VERSION 5.7 ;
  NOWIREEXTENSIONATPIN ON ;
  DIVIDERCHAR "/" ;
  BUSBITCHARS "[]" ;
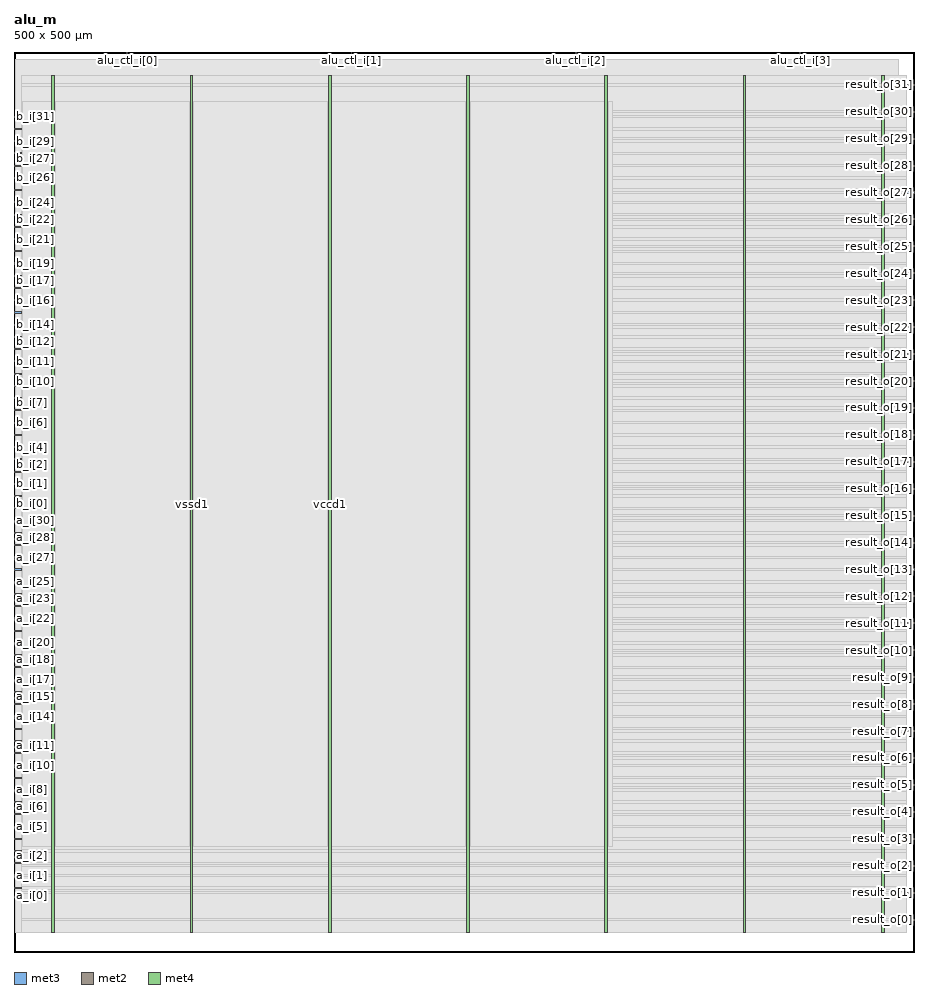
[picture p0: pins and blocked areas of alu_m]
MACRO alu_m
  CLASS BLOCK ;
  FOREIGN alu_m ;
  ORIGIN 0.000 0.000 ;
  SIZE 500.000 BY 500.000 ;
  PIN a_i[0]
    DIRECTION INPUT ;
    USE SIGNAL ;
    ANTENNAGATEAREA 0.213000 ;
    PORT
      LAYER met3 ;
        RECT 0.000 35.400 4.000 36.000 ;
    END
  END a_i[0]
  PIN a_i[10]
    DIRECTION INPUT ;
    USE SIGNAL ;
    ANTENNAGATEAREA 0.196500 ;
    PORT
      LAYER met3 ;
        RECT 0.000 103.400 4.000 104.000 ;
    END
  END a_i[10]
  PIN a_i[11]
    DIRECTION INPUT ;
    USE SIGNAL ;
    ANTENNAGATEAREA 0.196500 ;
    PORT
      LAYER met3 ;
        RECT 0.000 110.200 4.000 110.800 ;
    END
  END a_i[11]
  PIN a_i[12]
    DIRECTION INPUT ;
    USE SIGNAL ;
    ANTENNAGATEAREA 0.213000 ;
    PORT
      LAYER met3 ;
        RECT 0.000 117.000 4.000 117.600 ;
    END
  END a_i[12]
  PIN a_i[13]
    DIRECTION INPUT ;
    USE SIGNAL ;
    ANTENNAGATEAREA 0.213000 ;
    PORT
      LAYER met3 ;
        RECT 0.000 123.800 4.000 124.400 ;
    END
  END a_i[13]
  PIN a_i[14]
    DIRECTION INPUT ;
    USE SIGNAL ;
    ANTENNAGATEAREA 0.196500 ;
    PORT
      LAYER met3 ;
        RECT 0.000 130.600 4.000 131.200 ;
    END
  END a_i[14]
  PIN a_i[15]
    DIRECTION INPUT ;
    USE SIGNAL ;
    ANTENNAGATEAREA 0.196500 ;
    PORT
      LAYER met3 ;
        RECT 0.000 137.400 4.000 138.000 ;
    END
  END a_i[15]
  PIN a_i[16]
    DIRECTION INPUT ;
    USE SIGNAL ;
    ANTENNAGATEAREA 0.196500 ;
    PORT
      LAYER met3 ;
        RECT 0.000 144.200 4.000 144.800 ;
    END
  END a_i[16]
  PIN a_i[17]
    DIRECTION INPUT ;
    USE SIGNAL ;
    ANTENNAGATEAREA 0.196500 ;
    PORT
      LAYER met3 ;
        RECT 0.000 151.000 4.000 151.600 ;
    END
  END a_i[17]
  PIN a_i[18]
    DIRECTION INPUT ;
    USE SIGNAL ;
    ANTENNAGATEAREA 0.196500 ;
    PORT
      LAYER met3 ;
        RECT 0.000 157.800 4.000 158.400 ;
    END
  END a_i[18]
  PIN a_i[19]
    DIRECTION INPUT ;
    USE SIGNAL ;
    ANTENNAGATEAREA 0.196500 ;
    PORT
      LAYER met3 ;
        RECT 0.000 164.600 4.000 165.200 ;
    END
  END a_i[19]
  PIN a_i[1]
    DIRECTION INPUT ;
    USE SIGNAL ;
    ANTENNAGATEAREA 0.247500 ;
    PORT
      LAYER met3 ;
        RECT 0.000 42.200 4.000 42.800 ;
    END
  END a_i[1]
  PIN a_i[20]
    DIRECTION INPUT ;
    USE SIGNAL ;
    ANTENNAGATEAREA 0.196500 ;
    PORT
      LAYER met3 ;
        RECT 0.000 171.400 4.000 172.000 ;
    END
  END a_i[20]
  PIN a_i[21]
    DIRECTION INPUT ;
    USE SIGNAL ;
    ANTENNAGATEAREA 0.196500 ;
    PORT
      LAYER met3 ;
        RECT 0.000 178.200 4.000 178.800 ;
    END
  END a_i[21]
  PIN a_i[22]
    DIRECTION INPUT ;
    USE SIGNAL ;
    ANTENNAGATEAREA 0.196500 ;
    PORT
      LAYER met3 ;
        RECT 0.000 185.000 4.000 185.600 ;
    END
  END a_i[22]
  PIN a_i[23]
    DIRECTION INPUT ;
    USE SIGNAL ;
    ANTENNAGATEAREA 0.196500 ;
    PORT
      LAYER met3 ;
        RECT 0.000 191.800 4.000 192.400 ;
    END
  END a_i[23]
  PIN a_i[24]
    DIRECTION INPUT ;
    USE SIGNAL ;
    ANTENNAGATEAREA 0.196500 ;
    PORT
      LAYER met3 ;
        RECT 0.000 198.600 4.000 199.200 ;
    END
  END a_i[24]
  PIN a_i[25]
    DIRECTION INPUT ;
    USE SIGNAL ;
    ANTENNAGATEAREA 0.247500 ;
    PORT
      LAYER met3 ;
        RECT 0.000 205.400 4.000 206.000 ;
    END
  END a_i[25]
  PIN a_i[26]
    DIRECTION INPUT ;
    USE SIGNAL ;
    ANTENNAGATEAREA 0.213000 ;
    PORT
      LAYER met3 ;
        RECT 0.000 212.200 4.000 212.800 ;
    END
  END a_i[26]
  PIN a_i[27]
    DIRECTION INPUT ;
    USE SIGNAL ;
    ANTENNAGATEAREA 0.159000 ;
    PORT
      LAYER met3 ;
        RECT 0.000 219.000 4.000 219.600 ;
    END
  END a_i[27]
  PIN a_i[28]
    DIRECTION INPUT ;
    USE SIGNAL ;
    ANTENNAGATEAREA 0.159000 ;
    PORT
      LAYER met3 ;
        RECT 0.000 225.800 4.000 226.400 ;
    END
  END a_i[28]
  PIN a_i[29]
    DIRECTION INPUT ;
    USE SIGNAL ;
    ANTENNAGATEAREA 0.213000 ;
    PORT
      LAYER met3 ;
        RECT 0.000 232.600 4.000 233.200 ;
    END
  END a_i[29]
  PIN a_i[2]
    DIRECTION INPUT ;
    USE SIGNAL ;
    ANTENNAGATEAREA 0.159000 ;
    PORT
      LAYER met3 ;
        RECT 0.000 49.000 4.000 49.600 ;
    END
  END a_i[2]
  PIN a_i[30]
    DIRECTION INPUT ;
    USE SIGNAL ;
    ANTENNAGATEAREA 0.159000 ;
    PORT
      LAYER met3 ;
        RECT 0.000 239.400 4.000 240.000 ;
    END
  END a_i[30]
  PIN a_i[31]
    DIRECTION INPUT ;
    USE SIGNAL ;
    ANTENNAGATEAREA 0.213000 ;
    PORT
      LAYER met3 ;
        RECT 0.000 246.200 4.000 246.800 ;
    END
  END a_i[31]
  PIN a_i[3]
    DIRECTION INPUT ;
    USE SIGNAL ;
    ANTENNAGATEAREA 0.213000 ;
    PORT
      LAYER met3 ;
        RECT 0.000 55.800 4.000 56.400 ;
    END
  END a_i[3]
  PIN a_i[4]
    DIRECTION INPUT ;
    USE SIGNAL ;
    ANTENNAGATEAREA 0.159000 ;
    PORT
      LAYER met3 ;
        RECT 0.000 62.600 4.000 63.200 ;
    END
  END a_i[4]
  PIN a_i[5]
    DIRECTION INPUT ;
    USE SIGNAL ;
    ANTENNAGATEAREA 0.159000 ;
    PORT
      LAYER met3 ;
        RECT 0.000 69.400 4.000 70.000 ;
    END
  END a_i[5]
  PIN a_i[6]
    DIRECTION INPUT ;
    USE SIGNAL ;
    ANTENNAGATEAREA 0.213000 ;
    PORT
      LAYER met3 ;
        RECT 0.000 76.200 4.000 76.800 ;
    END
  END a_i[6]
  PIN a_i[7]
    DIRECTION INPUT ;
    USE SIGNAL ;
    ANTENNAGATEAREA 0.213000 ;
    PORT
      LAYER met3 ;
        RECT 0.000 83.000 4.000 83.600 ;
    END
  END a_i[7]
  PIN a_i[8]
    DIRECTION INPUT ;
    USE SIGNAL ;
    ANTENNAGATEAREA 0.213000 ;
    PORT
      LAYER met3 ;
        RECT 0.000 89.800 4.000 90.400 ;
    END
  END a_i[8]
  PIN a_i[9]
    DIRECTION INPUT ;
    USE SIGNAL ;
    ANTENNAGATEAREA 0.196500 ;
    PORT
      LAYER met3 ;
        RECT 0.000 96.600 4.000 97.200 ;
    END
  END a_i[9]
  PIN alu_ctl_i[0]
    DIRECTION INPUT ;
    USE SIGNAL ;
    ANTENNAGATEAREA 0.213000 ;
    PORT
      LAYER met2 ;
        RECT 62.650 496.000 62.930 500.000 ;
    END
  END alu_ctl_i[0]
  PIN alu_ctl_i[1]
    DIRECTION INPUT ;
    USE SIGNAL ;
    ANTENNAGATEAREA 0.213000 ;
    PORT
      LAYER met2 ;
        RECT 187.310 496.000 187.590 500.000 ;
    END
  END alu_ctl_i[1]
  PIN alu_ctl_i[2]
    DIRECTION INPUT ;
    USE SIGNAL ;
    ANTENNAGATEAREA 0.213000 ;
    PORT
      LAYER met2 ;
        RECT 311.970 496.000 312.250 500.000 ;
    END
  END alu_ctl_i[2]
  PIN alu_ctl_i[3]
    DIRECTION INPUT ;
    USE SIGNAL ;
    ANTENNAGATEAREA 0.213000 ;
    PORT
      LAYER met2 ;
        RECT 436.630 496.000 436.910 500.000 ;
    END
  END alu_ctl_i[3]
  PIN b_i[0]
    DIRECTION INPUT ;
    USE SIGNAL ;
    ANTENNAGATEAREA 0.196500 ;
    PORT
      LAYER met3 ;
        RECT 0.000 253.000 4.000 253.600 ;
    END
  END b_i[0]
  PIN b_i[10]
    DIRECTION INPUT ;
    USE SIGNAL ;
    ANTENNAGATEAREA 0.213000 ;
    PORT
      LAYER met3 ;
        RECT 0.000 321.000 4.000 321.600 ;
    END
  END b_i[10]
  PIN b_i[11]
    DIRECTION INPUT ;
    USE SIGNAL ;
    ANTENNAGATEAREA 0.159000 ;
    PORT
      LAYER met3 ;
        RECT 0.000 327.800 4.000 328.400 ;
    END
  END b_i[11]
  PIN b_i[12]
    DIRECTION INPUT ;
    USE SIGNAL ;
    ANTENNAGATEAREA 0.213000 ;
    PORT
      LAYER met3 ;
        RECT 0.000 334.600 4.000 335.200 ;
    END
  END b_i[12]
  PIN b_i[13]
    DIRECTION INPUT ;
    USE SIGNAL ;
    ANTENNAGATEAREA 0.213000 ;
    PORT
      LAYER met3 ;
        RECT 0.000 341.400 4.000 342.000 ;
    END
  END b_i[13]
  PIN b_i[14]
    DIRECTION INPUT ;
    USE SIGNAL ;
    ANTENNAGATEAREA 0.159000 ;
    PORT
      LAYER met3 ;
        RECT 0.000 348.200 4.000 348.800 ;
    END
  END b_i[14]
  PIN b_i[15]
    DIRECTION INPUT ;
    USE SIGNAL ;
    ANTENNAGATEAREA 0.159000 ;
    PORT
      LAYER met3 ;
        RECT 0.000 355.000 4.000 355.600 ;
    END
  END b_i[15]
  PIN b_i[16]
    DIRECTION INPUT ;
    USE SIGNAL ;
    ANTENNAGATEAREA 0.159000 ;
    PORT
      LAYER met3 ;
        RECT 0.000 361.800 4.000 362.400 ;
    END
  END b_i[16]
  PIN b_i[17]
    DIRECTION INPUT ;
    USE SIGNAL ;
    ANTENNAGATEAREA 0.196500 ;
    PORT
      LAYER met3 ;
        RECT 0.000 368.600 4.000 369.200 ;
    END
  END b_i[17]
  PIN b_i[18]
    DIRECTION INPUT ;
    USE SIGNAL ;
    ANTENNAGATEAREA 0.196500 ;
    PORT
      LAYER met3 ;
        RECT 0.000 375.400 4.000 376.000 ;
    END
  END b_i[18]
  PIN b_i[19]
    DIRECTION INPUT ;
    USE SIGNAL ;
    ANTENNAGATEAREA 0.196500 ;
    PORT
      LAYER met3 ;
        RECT 0.000 382.200 4.000 382.800 ;
    END
  END b_i[19]
  PIN b_i[1]
    DIRECTION INPUT ;
    USE SIGNAL ;
    ANTENNAGATEAREA 0.196500 ;
    PORT
      LAYER met3 ;
        RECT 0.000 259.800 4.000 260.400 ;
    END
  END b_i[1]
  PIN b_i[20]
    DIRECTION INPUT ;
    USE SIGNAL ;
    ANTENNAGATEAREA 0.196500 ;
    PORT
      LAYER met3 ;
        RECT 0.000 389.000 4.000 389.600 ;
    END
  END b_i[20]
  PIN b_i[21]
    DIRECTION INPUT ;
    USE SIGNAL ;
    ANTENNAGATEAREA 0.196500 ;
    PORT
      LAYER met3 ;
        RECT 0.000 395.800 4.000 396.400 ;
    END
  END b_i[21]
  PIN b_i[22]
    DIRECTION INPUT ;
    USE SIGNAL ;
    ANTENNAGATEAREA 0.196500 ;
    PORT
      LAYER met3 ;
        RECT 0.000 402.600 4.000 403.200 ;
    END
  END b_i[22]
  PIN b_i[23]
    DIRECTION INPUT ;
    USE SIGNAL ;
    ANTENNAGATEAREA 0.196500 ;
    PORT
      LAYER met3 ;
        RECT 0.000 409.400 4.000 410.000 ;
    END
  END b_i[23]
  PIN b_i[24]
    DIRECTION INPUT ;
    USE SIGNAL ;
    ANTENNAGATEAREA 0.196500 ;
    PORT
      LAYER met3 ;
        RECT 0.000 416.200 4.000 416.800 ;
    END
  END b_i[24]
  PIN b_i[25]
    DIRECTION INPUT ;
    USE SIGNAL ;
    ANTENNAGATEAREA 0.196500 ;
    PORT
      LAYER met3 ;
        RECT 0.000 423.000 4.000 423.600 ;
    END
  END b_i[25]
  PIN b_i[26]
    DIRECTION INPUT ;
    USE SIGNAL ;
    ANTENNAGATEAREA 0.247500 ;
    PORT
      LAYER met3 ;
        RECT 0.000 429.800 4.000 430.400 ;
    END
  END b_i[26]
  PIN b_i[27]
    DIRECTION INPUT ;
    USE SIGNAL ;
    ANTENNAGATEAREA 0.247500 ;
    PORT
      LAYER met3 ;
        RECT 0.000 436.600 4.000 437.200 ;
    END
  END b_i[27]
  PIN b_i[28]
    DIRECTION INPUT ;
    USE SIGNAL ;
    ANTENNAGATEAREA 0.196500 ;
    PORT
      LAYER met3 ;
        RECT 0.000 443.400 4.000 444.000 ;
    END
  END b_i[28]
  PIN b_i[29]
    DIRECTION INPUT ;
    USE SIGNAL ;
    ANTENNAGATEAREA 0.159000 ;
    PORT
      LAYER met3 ;
        RECT 0.000 450.200 4.000 450.800 ;
    END
  END b_i[29]
  PIN b_i[2]
    DIRECTION INPUT ;
    USE SIGNAL ;
    ANTENNAGATEAREA 0.159000 ;
    PORT
      LAYER met3 ;
        RECT 0.000 266.600 4.000 267.200 ;
    END
  END b_i[2]
  PIN b_i[30]
    DIRECTION INPUT ;
    USE SIGNAL ;
    ANTENNAGATEAREA 0.196500 ;
    PORT
      LAYER met3 ;
        RECT 0.000 457.000 4.000 457.600 ;
    END
  END b_i[30]
  PIN b_i[31]
    DIRECTION INPUT ;
    USE SIGNAL ;
    ANTENNAGATEAREA 0.213000 ;
    PORT
      LAYER met3 ;
        RECT 0.000 463.800 4.000 464.400 ;
    END
  END b_i[31]
  PIN b_i[3]
    DIRECTION INPUT ;
    USE SIGNAL ;
    ANTENNAGATEAREA 0.159000 ;
    PORT
      LAYER met3 ;
        RECT 0.000 273.400 4.000 274.000 ;
    END
  END b_i[3]
  PIN b_i[4]
    DIRECTION INPUT ;
    USE SIGNAL ;
    ANTENNAGATEAREA 0.213000 ;
    PORT
      LAYER met3 ;
        RECT 0.000 280.200 4.000 280.800 ;
    END
  END b_i[4]
  PIN b_i[5]
    DIRECTION INPUT ;
    USE SIGNAL ;
    ANTENNAGATEAREA 0.213000 ;
    PORT
      LAYER met3 ;
        RECT 0.000 287.000 4.000 287.600 ;
    END
  END b_i[5]
  PIN b_i[6]
    DIRECTION INPUT ;
    USE SIGNAL ;
    ANTENNAGATEAREA 0.247500 ;
    PORT
      LAYER met3 ;
        RECT 0.000 293.800 4.000 294.400 ;
    END
  END b_i[6]
  PIN b_i[7]
    DIRECTION INPUT ;
    USE SIGNAL ;
    ANTENNAGATEAREA 0.213000 ;
    PORT
      LAYER met3 ;
        RECT 0.000 300.600 4.000 301.200 ;
    END
  END b_i[7]
  PIN b_i[8]
    DIRECTION INPUT ;
    USE SIGNAL ;
    ANTENNAGATEAREA 0.213000 ;
    PORT
      LAYER met3 ;
        RECT 0.000 307.400 4.000 308.000 ;
    END
  END b_i[8]
  PIN b_i[9]
    DIRECTION INPUT ;
    USE SIGNAL ;
    ANTENNAGATEAREA 0.247500 ;
    PORT
      LAYER met3 ;
        RECT 0.000 314.200 4.000 314.800 ;
    END
  END b_i[9]
  PIN result_o[0]
    DIRECTION OUTPUT TRISTATE ;
    USE SIGNAL ;
    ANTENNADIFFAREA 2.673000 ;
    PORT
      LAYER met3 ;
        RECT 496.000 17.720 500.000 18.320 ;
    END
  END result_o[0]
  PIN result_o[10]
    DIRECTION OUTPUT TRISTATE ;
    USE SIGNAL ;
    ANTENNADIFFAREA 2.673000 ;
    PORT
      LAYER met3 ;
        RECT 496.000 167.320 500.000 167.920 ;
    END
  END result_o[10]
  PIN result_o[11]
    DIRECTION OUTPUT TRISTATE ;
    USE SIGNAL ;
    ANTENNADIFFAREA 2.673000 ;
    PORT
      LAYER met3 ;
        RECT 496.000 182.280 500.000 182.880 ;
    END
  END result_o[11]
  PIN result_o[12]
    DIRECTION OUTPUT TRISTATE ;
    USE SIGNAL ;
    ANTENNADIFFAREA 2.673000 ;
    PORT
      LAYER met3 ;
        RECT 496.000 197.240 500.000 197.840 ;
    END
  END result_o[12]
  PIN result_o[13]
    DIRECTION OUTPUT TRISTATE ;
    USE SIGNAL ;
    ANTENNADIFFAREA 2.673000 ;
    PORT
      LAYER met3 ;
        RECT 496.000 212.200 500.000 212.800 ;
    END
  END result_o[13]
  PIN result_o[14]
    DIRECTION OUTPUT TRISTATE ;
    USE SIGNAL ;
    ANTENNADIFFAREA 2.673000 ;
    PORT
      LAYER met3 ;
        RECT 496.000 227.160 500.000 227.760 ;
    END
  END result_o[14]
  PIN result_o[15]
    DIRECTION OUTPUT TRISTATE ;
    USE SIGNAL ;
    ANTENNADIFFAREA 2.673000 ;
    PORT
      LAYER met3 ;
        RECT 496.000 242.120 500.000 242.720 ;
    END
  END result_o[15]
  PIN result_o[16]
    DIRECTION OUTPUT TRISTATE ;
    USE SIGNAL ;
    ANTENNADIFFAREA 2.673000 ;
    PORT
      LAYER met3 ;
        RECT 496.000 257.080 500.000 257.680 ;
    END
  END result_o[16]
  PIN result_o[17]
    DIRECTION OUTPUT TRISTATE ;
    USE SIGNAL ;
    ANTENNADIFFAREA 2.673000 ;
    PORT
      LAYER met3 ;
        RECT 496.000 272.040 500.000 272.640 ;
    END
  END result_o[17]
  PIN result_o[18]
    DIRECTION OUTPUT TRISTATE ;
    USE SIGNAL ;
    ANTENNADIFFAREA 2.673000 ;
    PORT
      LAYER met3 ;
        RECT 496.000 287.000 500.000 287.600 ;
    END
  END result_o[18]
  PIN result_o[19]
    DIRECTION OUTPUT TRISTATE ;
    USE SIGNAL ;
    ANTENNADIFFAREA 2.673000 ;
    PORT
      LAYER met3 ;
        RECT 496.000 301.960 500.000 302.560 ;
    END
  END result_o[19]
  PIN result_o[1]
    DIRECTION OUTPUT TRISTATE ;
    USE SIGNAL ;
    ANTENNADIFFAREA 2.673000 ;
    PORT
      LAYER met3 ;
        RECT 496.000 32.680 500.000 33.280 ;
    END
  END result_o[1]
  PIN result_o[20]
    DIRECTION OUTPUT TRISTATE ;
    USE SIGNAL ;
    ANTENNADIFFAREA 2.673000 ;
    PORT
      LAYER met3 ;
        RECT 496.000 316.920 500.000 317.520 ;
    END
  END result_o[20]
  PIN result_o[21]
    DIRECTION OUTPUT TRISTATE ;
    USE SIGNAL ;
    ANTENNADIFFAREA 2.673000 ;
    PORT
      LAYER met3 ;
        RECT 496.000 331.880 500.000 332.480 ;
    END
  END result_o[21]
  PIN result_o[22]
    DIRECTION OUTPUT TRISTATE ;
    USE SIGNAL ;
    ANTENNADIFFAREA 2.673000 ;
    PORT
      LAYER met3 ;
        RECT 496.000 346.840 500.000 347.440 ;
    END
  END result_o[22]
  PIN result_o[23]
    DIRECTION OUTPUT TRISTATE ;
    USE SIGNAL ;
    ANTENNADIFFAREA 2.673000 ;
    PORT
      LAYER met3 ;
        RECT 496.000 361.800 500.000 362.400 ;
    END
  END result_o[23]
  PIN result_o[24]
    DIRECTION OUTPUT TRISTATE ;
    USE SIGNAL ;
    ANTENNADIFFAREA 2.673000 ;
    PORT
      LAYER met3 ;
        RECT 496.000 376.760 500.000 377.360 ;
    END
  END result_o[24]
  PIN result_o[25]
    DIRECTION OUTPUT TRISTATE ;
    USE SIGNAL ;
    ANTENNADIFFAREA 2.673000 ;
    PORT
      LAYER met3 ;
        RECT 496.000 391.720 500.000 392.320 ;
    END
  END result_o[25]
  PIN result_o[26]
    DIRECTION OUTPUT TRISTATE ;
    USE SIGNAL ;
    ANTENNADIFFAREA 2.673000 ;
    PORT
      LAYER met3 ;
        RECT 496.000 406.680 500.000 407.280 ;
    END
  END result_o[26]
  PIN result_o[27]
    DIRECTION OUTPUT TRISTATE ;
    USE SIGNAL ;
    ANTENNADIFFAREA 2.673000 ;
    PORT
      LAYER met3 ;
        RECT 496.000 421.640 500.000 422.240 ;
    END
  END result_o[27]
  PIN result_o[28]
    DIRECTION OUTPUT TRISTATE ;
    USE SIGNAL ;
    ANTENNADIFFAREA 2.673000 ;
    PORT
      LAYER met3 ;
        RECT 496.000 436.600 500.000 437.200 ;
    END
  END result_o[28]
  PIN result_o[29]
    DIRECTION OUTPUT TRISTATE ;
    USE SIGNAL ;
    ANTENNADIFFAREA 2.673000 ;
    PORT
      LAYER met3 ;
        RECT 496.000 451.560 500.000 452.160 ;
    END
  END result_o[29]
  PIN result_o[2]
    DIRECTION OUTPUT TRISTATE ;
    USE SIGNAL ;
    ANTENNADIFFAREA 2.673000 ;
    PORT
      LAYER met3 ;
        RECT 496.000 47.640 500.000 48.240 ;
    END
  END result_o[2]
  PIN result_o[30]
    DIRECTION OUTPUT TRISTATE ;
    USE SIGNAL ;
    ANTENNADIFFAREA 2.673000 ;
    PORT
      LAYER met3 ;
        RECT 496.000 466.520 500.000 467.120 ;
    END
  END result_o[30]
  PIN result_o[31]
    DIRECTION OUTPUT TRISTATE ;
    USE SIGNAL ;
    ANTENNADIFFAREA 2.673000 ;
    PORT
      LAYER met3 ;
        RECT 496.000 481.480 500.000 482.080 ;
    END
  END result_o[31]
  PIN result_o[3]
    DIRECTION OUTPUT TRISTATE ;
    USE SIGNAL ;
    ANTENNADIFFAREA 2.673000 ;
    PORT
      LAYER met3 ;
        RECT 496.000 62.600 500.000 63.200 ;
    END
  END result_o[3]
  PIN result_o[4]
    DIRECTION OUTPUT TRISTATE ;
    USE SIGNAL ;
    ANTENNADIFFAREA 2.673000 ;
    PORT
      LAYER met3 ;
        RECT 496.000 77.560 500.000 78.160 ;
    END
  END result_o[4]
  PIN result_o[5]
    DIRECTION OUTPUT TRISTATE ;
    USE SIGNAL ;
    ANTENNADIFFAREA 2.673000 ;
    PORT
      LAYER met3 ;
        RECT 496.000 92.520 500.000 93.120 ;
    END
  END result_o[5]
  PIN result_o[6]
    DIRECTION OUTPUT TRISTATE ;
    USE SIGNAL ;
    ANTENNADIFFAREA 2.673000 ;
    PORT
      LAYER met3 ;
        RECT 496.000 107.480 500.000 108.080 ;
    END
  END result_o[6]
  PIN result_o[7]
    DIRECTION OUTPUT TRISTATE ;
    USE SIGNAL ;
    ANTENNADIFFAREA 2.673000 ;
    PORT
      LAYER met3 ;
        RECT 496.000 122.440 500.000 123.040 ;
    END
  END result_o[7]
  PIN result_o[8]
    DIRECTION OUTPUT TRISTATE ;
    USE SIGNAL ;
    ANTENNADIFFAREA 2.673000 ;
    PORT
      LAYER met3 ;
        RECT 496.000 137.400 500.000 138.000 ;
    END
  END result_o[8]
  PIN result_o[9]
    DIRECTION OUTPUT TRISTATE ;
    USE SIGNAL ;
    ANTENNADIFFAREA 2.673000 ;
    PORT
      LAYER met3 ;
        RECT 496.000 152.360 500.000 152.960 ;
    END
  END result_o[9]
  PIN vccd1
    DIRECTION INOUT ;
    USE POWER ;
    PORT
      LAYER met4 ;
        RECT 21.040 10.640 22.640 487.120 ;
    END
    PORT
      LAYER met4 ;
        RECT 174.640 10.640 176.240 487.120 ;
    END
    PORT
      LAYER met4 ;
        RECT 328.240 10.640 329.840 487.120 ;
    END
    PORT
      LAYER met4 ;
        RECT 481.840 10.640 483.440 487.120 ;
    END
  END vccd1
  PIN vssd1
    DIRECTION INOUT ;
    USE GROUND ;
    PORT
      LAYER met4 ;
        RECT 97.840 10.640 99.440 487.120 ;
    END
    PORT
      LAYER met4 ;
        RECT 251.440 10.640 253.040 487.120 ;
    END
    PORT
      LAYER met4 ;
        RECT 405.040 10.640 406.640 487.120 ;
    END
  END vssd1
  OBS
      LAYER li1 ;
        RECT 5.520 10.795 494.040 486.965 ;
      LAYER met1 ;
        RECT 0.990 10.640 494.040 487.120 ;
      LAYER met2 ;
        RECT 1.020 495.720 62.370 496.000 ;
        RECT 63.210 495.720 187.030 496.000 ;
        RECT 187.870 495.720 311.690 496.000 ;
        RECT 312.530 495.720 436.350 496.000 ;
        RECT 437.190 495.720 491.650 496.000 ;
        RECT 1.020 10.695 491.650 495.720 ;
      LAYER met3 ;
        RECT 3.990 482.480 496.000 487.045 ;
        RECT 3.990 481.080 495.600 482.480 ;
        RECT 3.990 467.520 496.000 481.080 ;
        RECT 3.990 466.120 495.600 467.520 ;
        RECT 3.990 464.800 496.000 466.120 ;
        RECT 4.400 463.400 496.000 464.800 ;
        RECT 3.990 458.000 496.000 463.400 ;
        RECT 4.400 456.600 496.000 458.000 ;
        RECT 3.990 452.560 496.000 456.600 ;
        RECT 3.990 451.200 495.600 452.560 ;
        RECT 4.400 451.160 495.600 451.200 ;
        RECT 4.400 449.800 496.000 451.160 ;
        RECT 3.990 444.400 496.000 449.800 ;
        RECT 4.400 443.000 496.000 444.400 ;
        RECT 3.990 437.600 496.000 443.000 ;
        RECT 4.400 436.200 495.600 437.600 ;
        RECT 3.990 430.800 496.000 436.200 ;
        RECT 4.400 429.400 496.000 430.800 ;
        RECT 3.990 424.000 496.000 429.400 ;
        RECT 4.400 422.640 496.000 424.000 ;
        RECT 4.400 422.600 495.600 422.640 ;
        RECT 3.990 421.240 495.600 422.600 ;
        RECT 3.990 417.200 496.000 421.240 ;
        RECT 4.400 415.800 496.000 417.200 ;
        RECT 3.990 410.400 496.000 415.800 ;
        RECT 4.400 409.000 496.000 410.400 ;
        RECT 3.990 407.680 496.000 409.000 ;
        RECT 3.990 406.280 495.600 407.680 ;
        RECT 3.990 403.600 496.000 406.280 ;
        RECT 4.400 402.200 496.000 403.600 ;
        RECT 3.990 396.800 496.000 402.200 ;
        RECT 4.400 395.400 496.000 396.800 ;
        RECT 3.990 392.720 496.000 395.400 ;
        RECT 3.990 391.320 495.600 392.720 ;
        RECT 3.990 390.000 496.000 391.320 ;
        RECT 4.400 388.600 496.000 390.000 ;
        RECT 3.990 383.200 496.000 388.600 ;
        RECT 4.400 381.800 496.000 383.200 ;
        RECT 3.990 377.760 496.000 381.800 ;
        RECT 3.990 376.400 495.600 377.760 ;
        RECT 4.400 376.360 495.600 376.400 ;
        RECT 4.400 375.000 496.000 376.360 ;
        RECT 3.990 369.600 496.000 375.000 ;
        RECT 4.400 368.200 496.000 369.600 ;
        RECT 3.990 362.800 496.000 368.200 ;
        RECT 4.400 361.400 495.600 362.800 ;
        RECT 3.990 356.000 496.000 361.400 ;
        RECT 4.400 354.600 496.000 356.000 ;
        RECT 3.990 349.200 496.000 354.600 ;
        RECT 4.400 347.840 496.000 349.200 ;
        RECT 4.400 347.800 495.600 347.840 ;
        RECT 3.990 346.440 495.600 347.800 ;
        RECT 3.990 342.400 496.000 346.440 ;
        RECT 4.400 341.000 496.000 342.400 ;
        RECT 3.990 335.600 496.000 341.000 ;
        RECT 4.400 334.200 496.000 335.600 ;
        RECT 3.990 332.880 496.000 334.200 ;
        RECT 3.990 331.480 495.600 332.880 ;
        RECT 3.990 328.800 496.000 331.480 ;
        RECT 4.400 327.400 496.000 328.800 ;
        RECT 3.990 322.000 496.000 327.400 ;
        RECT 4.400 320.600 496.000 322.000 ;
        RECT 3.990 317.920 496.000 320.600 ;
        RECT 3.990 316.520 495.600 317.920 ;
        RECT 3.990 315.200 496.000 316.520 ;
        RECT 4.400 313.800 496.000 315.200 ;
        RECT 3.990 308.400 496.000 313.800 ;
        RECT 4.400 307.000 496.000 308.400 ;
        RECT 3.990 302.960 496.000 307.000 ;
        RECT 3.990 301.600 495.600 302.960 ;
        RECT 4.400 301.560 495.600 301.600 ;
        RECT 4.400 300.200 496.000 301.560 ;
        RECT 3.990 294.800 496.000 300.200 ;
        RECT 4.400 293.400 496.000 294.800 ;
        RECT 3.990 288.000 496.000 293.400 ;
        RECT 4.400 286.600 495.600 288.000 ;
        RECT 3.990 281.200 496.000 286.600 ;
        RECT 4.400 279.800 496.000 281.200 ;
        RECT 3.990 274.400 496.000 279.800 ;
        RECT 4.400 273.040 496.000 274.400 ;
        RECT 4.400 273.000 495.600 273.040 ;
        RECT 3.990 271.640 495.600 273.000 ;
        RECT 3.990 267.600 496.000 271.640 ;
        RECT 4.400 266.200 496.000 267.600 ;
        RECT 3.990 260.800 496.000 266.200 ;
        RECT 4.400 259.400 496.000 260.800 ;
        RECT 3.990 258.080 496.000 259.400 ;
        RECT 3.990 256.680 495.600 258.080 ;
        RECT 3.990 254.000 496.000 256.680 ;
        RECT 4.400 252.600 496.000 254.000 ;
        RECT 3.990 247.200 496.000 252.600 ;
        RECT 4.400 245.800 496.000 247.200 ;
        RECT 3.990 243.120 496.000 245.800 ;
        RECT 3.990 241.720 495.600 243.120 ;
        RECT 3.990 240.400 496.000 241.720 ;
        RECT 4.400 239.000 496.000 240.400 ;
        RECT 3.990 233.600 496.000 239.000 ;
        RECT 4.400 232.200 496.000 233.600 ;
        RECT 3.990 228.160 496.000 232.200 ;
        RECT 3.990 226.800 495.600 228.160 ;
        RECT 4.400 226.760 495.600 226.800 ;
        RECT 4.400 225.400 496.000 226.760 ;
        RECT 3.990 220.000 496.000 225.400 ;
        RECT 4.400 218.600 496.000 220.000 ;
        RECT 3.990 213.200 496.000 218.600 ;
        RECT 4.400 211.800 495.600 213.200 ;
        RECT 3.990 206.400 496.000 211.800 ;
        RECT 4.400 205.000 496.000 206.400 ;
        RECT 3.990 199.600 496.000 205.000 ;
        RECT 4.400 198.240 496.000 199.600 ;
        RECT 4.400 198.200 495.600 198.240 ;
        RECT 3.990 196.840 495.600 198.200 ;
        RECT 3.990 192.800 496.000 196.840 ;
        RECT 4.400 191.400 496.000 192.800 ;
        RECT 3.990 186.000 496.000 191.400 ;
        RECT 4.400 184.600 496.000 186.000 ;
        RECT 3.990 183.280 496.000 184.600 ;
        RECT 3.990 181.880 495.600 183.280 ;
        RECT 3.990 179.200 496.000 181.880 ;
        RECT 4.400 177.800 496.000 179.200 ;
        RECT 3.990 172.400 496.000 177.800 ;
        RECT 4.400 171.000 496.000 172.400 ;
        RECT 3.990 168.320 496.000 171.000 ;
        RECT 3.990 166.920 495.600 168.320 ;
        RECT 3.990 165.600 496.000 166.920 ;
        RECT 4.400 164.200 496.000 165.600 ;
        RECT 3.990 158.800 496.000 164.200 ;
        RECT 4.400 157.400 496.000 158.800 ;
        RECT 3.990 153.360 496.000 157.400 ;
        RECT 3.990 152.000 495.600 153.360 ;
        RECT 4.400 151.960 495.600 152.000 ;
        RECT 4.400 150.600 496.000 151.960 ;
        RECT 3.990 145.200 496.000 150.600 ;
        RECT 4.400 143.800 496.000 145.200 ;
        RECT 3.990 138.400 496.000 143.800 ;
        RECT 4.400 137.000 495.600 138.400 ;
        RECT 3.990 131.600 496.000 137.000 ;
        RECT 4.400 130.200 496.000 131.600 ;
        RECT 3.990 124.800 496.000 130.200 ;
        RECT 4.400 123.440 496.000 124.800 ;
        RECT 4.400 123.400 495.600 123.440 ;
        RECT 3.990 122.040 495.600 123.400 ;
        RECT 3.990 118.000 496.000 122.040 ;
        RECT 4.400 116.600 496.000 118.000 ;
        RECT 3.990 111.200 496.000 116.600 ;
        RECT 4.400 109.800 496.000 111.200 ;
        RECT 3.990 108.480 496.000 109.800 ;
        RECT 3.990 107.080 495.600 108.480 ;
        RECT 3.990 104.400 496.000 107.080 ;
        RECT 4.400 103.000 496.000 104.400 ;
        RECT 3.990 97.600 496.000 103.000 ;
        RECT 4.400 96.200 496.000 97.600 ;
        RECT 3.990 93.520 496.000 96.200 ;
        RECT 3.990 92.120 495.600 93.520 ;
        RECT 3.990 90.800 496.000 92.120 ;
        RECT 4.400 89.400 496.000 90.800 ;
        RECT 3.990 84.000 496.000 89.400 ;
        RECT 4.400 82.600 496.000 84.000 ;
        RECT 3.990 78.560 496.000 82.600 ;
        RECT 3.990 77.200 495.600 78.560 ;
        RECT 4.400 77.160 495.600 77.200 ;
        RECT 4.400 75.800 496.000 77.160 ;
        RECT 3.990 70.400 496.000 75.800 ;
        RECT 4.400 69.000 496.000 70.400 ;
        RECT 3.990 63.600 496.000 69.000 ;
        RECT 4.400 62.200 495.600 63.600 ;
        RECT 3.990 56.800 496.000 62.200 ;
        RECT 4.400 55.400 496.000 56.800 ;
        RECT 3.990 50.000 496.000 55.400 ;
        RECT 4.400 48.640 496.000 50.000 ;
        RECT 4.400 48.600 495.600 48.640 ;
        RECT 3.990 47.240 495.600 48.600 ;
        RECT 3.990 43.200 496.000 47.240 ;
        RECT 4.400 41.800 496.000 43.200 ;
        RECT 3.990 36.400 496.000 41.800 ;
        RECT 4.400 35.000 496.000 36.400 ;
        RECT 3.990 33.680 496.000 35.000 ;
        RECT 3.990 32.280 495.600 33.680 ;
        RECT 3.990 18.720 496.000 32.280 ;
        RECT 3.990 17.320 495.600 18.720 ;
        RECT 3.990 10.715 496.000 17.320 ;
      LAYER met4 ;
        RECT 4.895 58.655 20.640 472.425 ;
        RECT 23.040 58.655 97.440 472.425 ;
        RECT 99.840 58.655 174.240 472.425 ;
        RECT 176.640 58.655 251.040 472.425 ;
        RECT 253.440 58.655 327.840 472.425 ;
        RECT 330.240 58.655 332.745 472.425 ;
  END
END alu_m
END LIBRARY

